One B-rep face of a CAD part: STEP entity #547.
In plain terms, the planar face has unit normal (1, 0, 0).
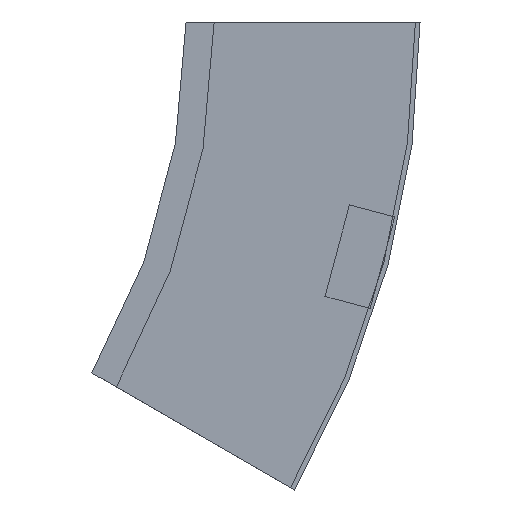
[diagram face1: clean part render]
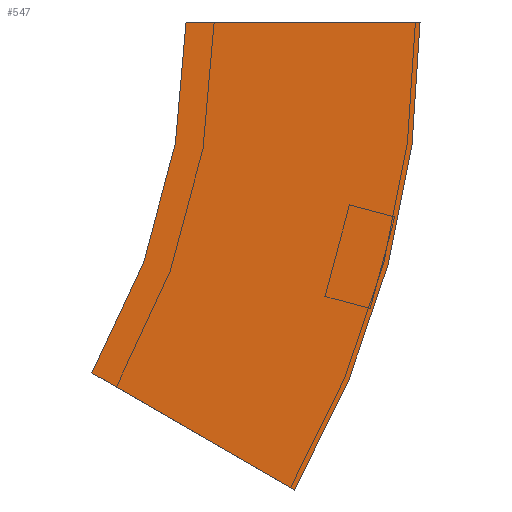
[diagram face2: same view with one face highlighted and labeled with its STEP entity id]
Its self-contained STEP definition (entity closure, numbers rounded to 3 decimals):
#10 = DIRECTION ( 'NONE',  ( 0., 0., 1. ) ) ;
#17 = LINE ( 'NONE', #63, #428 ) ;
#51 = CARTESIAN_POINT ( 'NONE',  ( 0., 40.192, -150. ) ) ;
#53 = CARTESIAN_POINT ( 'NONE',  ( 0., -100., 0. ) ) ;
#54 = EDGE_CURVE ( 'NONE', #162, #254, #324, .T. ) ;
#63 = CARTESIAN_POINT ( 'NONE',  ( 0., -100., 0. ) ) ;
#85 = DIRECTION ( 'NONE',  ( 1., 0., 0. ) ) ;
#88 = EDGE_CURVE ( 'NONE', #391, #162, #17, .T. ) ;
#134 = CARTESIAN_POINT ( 'NONE',  ( 0., 300., 0. ) ) ;
#138 = VECTOR ( 'NONE', #261, 1000. ) ;
#145 = CARTESIAN_POINT ( 'NONE',  ( 0., 0., 0. ) ) ;
#162 = VERTEX_POINT ( 'NONE', #145 ) ;
#169 = AXIS2_PLACEMENT_3D ( 'NONE', #298, #85, #470 ) ;
#181 = PLANE ( 'NONE',  #210 ) ;
#188 = DIRECTION ( 'NONE',  ( 0., 1., 0. ) ) ;
#210 = AXIS2_PLACEMENT_3D ( 'NONE', #53, #402, #10 ) ;
#212 = CARTESIAN_POINT ( 'NONE',  ( 0., -46.41, -200. ) ) ;
#222 = FACE_OUTER_BOUND ( 'NONE', #284, .T. ) ;
#254 = VERTEX_POINT ( 'NONE', #51 ) ;
#261 = DIRECTION ( 'NONE',  ( 0., 0.866, 0.5 ) ) ;
#284 = EDGE_LOOP ( 'NONE', ( #342, #440, #534, #325 ) ) ;
#290 = CARTESIAN_POINT ( 'NONE',  ( 0., -46.41, -200. ) ) ;
#298 = CARTESIAN_POINT ( 'NONE',  ( 0., 300., 0. ) ) ;
#324 = CIRCLE ( 'NONE', #395, 300. ) ;
#325 = ORIENTED_EDGE ( 'NONE', *, *, #432, .T. ) ;
#338 = LINE ( 'NONE', #290, #138 ) ;
#342 = ORIENTED_EDGE ( 'NONE', *, *, #54, .F. ) ;
#363 = CIRCLE ( 'NONE', #169, 400. ) ;
#367 = DIRECTION ( 'NONE',  ( 1., 0., 0. ) ) ;
#378 = CARTESIAN_POINT ( 'NONE',  ( 0., -100., 0. ) ) ;
#391 = VERTEX_POINT ( 'NONE', #378 ) ;
#395 = AXIS2_PLACEMENT_3D ( 'NONE', #134, #367, #484 ) ;
#400 = EDGE_CURVE ( 'NONE', #391, #454, #363, .T. ) ;
#402 = DIRECTION ( 'NONE',  ( -1., 0., 0. ) ) ;
#428 = VECTOR ( 'NONE', #188, 1000. ) ;
#432 = EDGE_CURVE ( 'NONE', #454, #254, #338, .T. ) ;
#440 = ORIENTED_EDGE ( 'NONE', *, *, #88, .F. ) ;
#454 = VERTEX_POINT ( 'NONE', #212 ) ;
#470 = DIRECTION ( 'NONE',  ( 0., -1., 0. ) ) ;
#484 = DIRECTION ( 'NONE',  ( 0., -1., 0. ) ) ;
#534 = ORIENTED_EDGE ( 'NONE', *, *, #400, .T. ) ;
#547 = ADVANCED_FACE ( 'NONE', ( #222 ), #181, .F. ) ;
